VERSION 5.8 ;
BUSBITCHARS "[]" ;
DIVIDERCHAR "/" ;
UNITS
    DATABASE MICRONS 1000 ;
END UNITS

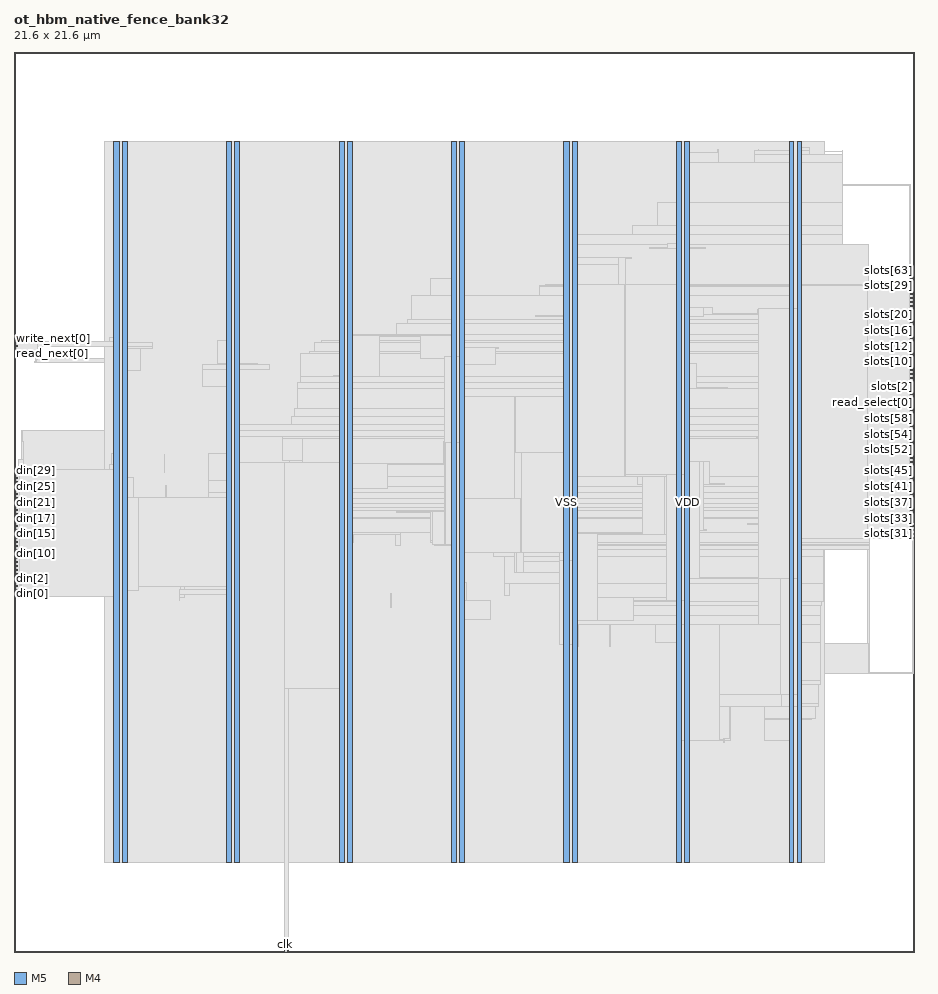
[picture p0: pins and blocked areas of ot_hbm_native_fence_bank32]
MACRO ot_hbm_native_fence_bank32
  FOREIGN ot_hbm_native_fence_bank32 0 0 ;
  CLASS BLOCK ;
  SIZE 21.6 BY 21.6 ;
  PIN clk
    DIRECTION INPUT ;
    USE SIGNAL ;
    PORT
      LAYER M5 ;
        RECT  6.48 0 6.504 0.084 ;
    END
  END clk
  PIN din[0]
    DIRECTION INPUT ;
    USE SIGNAL ;
    PORT
      LAYER M4 ;
        RECT  0 8.592 0.084 8.616 ;
    END
  END din[0]
  PIN din[10]
    DIRECTION INPUT ;
    USE SIGNAL ;
    PORT
      LAYER M4 ;
        RECT  0 9.552 0.084 9.576 ;
    END
  END din[10]
  PIN din[11]
    DIRECTION INPUT ;
    USE SIGNAL ;
    PORT
      LAYER M4 ;
        RECT  0 9.648 0.084 9.672 ;
    END
  END din[11]
  PIN din[12]
    DIRECTION INPUT ;
    USE SIGNAL ;
    PORT
      LAYER M4 ;
        RECT  0 9.744 0.084 9.768 ;
    END
  END din[12]
  PIN din[13]
    DIRECTION INPUT ;
    USE SIGNAL ;
    PORT
      LAYER M4 ;
        RECT  0 9.84 0.084 9.864 ;
    END
  END din[13]
  PIN din[14]
    DIRECTION INPUT ;
    USE SIGNAL ;
    PORT
      LAYER M4 ;
        RECT  0 9.936 0.084 9.96 ;
    END
  END din[14]
  PIN din[15]
    DIRECTION INPUT ;
    USE SIGNAL ;
    PORT
      LAYER M4 ;
        RECT  0 10.032 0.084 10.056 ;
    END
  END din[15]
  PIN din[16]
    DIRECTION INPUT ;
    USE SIGNAL ;
    PORT
      LAYER M4 ;
        RECT  0 10.128 0.084 10.152 ;
    END
  END din[16]
  PIN din[17]
    DIRECTION INPUT ;
    USE SIGNAL ;
    PORT
      LAYER M4 ;
        RECT  0 10.224 0.084 10.248 ;
    END
  END din[17]
  PIN din[18]
    DIRECTION INPUT ;
    USE SIGNAL ;
    PORT
      LAYER M4 ;
        RECT  0 10.32 0.084 10.344 ;
    END
  END din[18]
  PIN din[19]
    DIRECTION INPUT ;
    USE SIGNAL ;
    PORT
      LAYER M4 ;
        RECT  0 10.416 0.084 10.44 ;
    END
  END din[19]
  PIN din[1]
    DIRECTION INPUT ;
    USE SIGNAL ;
    PORT
      LAYER M4 ;
        RECT  0 8.688 0.084 8.712 ;
    END
  END din[1]
  PIN din[20]
    DIRECTION INPUT ;
    USE SIGNAL ;
    PORT
      LAYER M4 ;
        RECT  0 10.512 0.084 10.536 ;
    END
  END din[20]
  PIN din[21]
    DIRECTION INPUT ;
    USE SIGNAL ;
    PORT
      LAYER M4 ;
        RECT  0 10.608 0.084 10.632 ;
    END
  END din[21]
  PIN din[22]
    DIRECTION INPUT ;
    USE SIGNAL ;
    PORT
      LAYER M4 ;
        RECT  0 10.704 0.084 10.728 ;
    END
  END din[22]
  PIN din[23]
    DIRECTION INPUT ;
    USE SIGNAL ;
    PORT
      LAYER M4 ;
        RECT  0 10.8 0.084 10.824 ;
    END
  END din[23]
  PIN din[24]
    DIRECTION INPUT ;
    USE SIGNAL ;
    PORT
      LAYER M4 ;
        RECT  0 10.896 0.084 10.92 ;
    END
  END din[24]
  PIN din[25]
    DIRECTION INPUT ;
    USE SIGNAL ;
    PORT
      LAYER M4 ;
        RECT  0 10.992 0.084 11.016 ;
    END
  END din[25]
  PIN din[26]
    DIRECTION INPUT ;
    USE SIGNAL ;
    PORT
      LAYER M4 ;
        RECT  0 11.088 0.084 11.112 ;
    END
  END din[26]
  PIN din[27]
    DIRECTION INPUT ;
    USE SIGNAL ;
    PORT
      LAYER M4 ;
        RECT  0 11.184 0.084 11.208 ;
    END
  END din[27]
  PIN din[28]
    DIRECTION INPUT ;
    USE SIGNAL ;
    PORT
      LAYER M4 ;
        RECT  0 11.28 0.084 11.304 ;
    END
  END din[28]
  PIN din[29]
    DIRECTION INPUT ;
    USE SIGNAL ;
    PORT
      LAYER M4 ;
        RECT  0 11.376 0.084 11.4 ;
    END
  END din[29]
  PIN din[2]
    DIRECTION INPUT ;
    USE SIGNAL ;
    PORT
      LAYER M4 ;
        RECT  0 8.784 0.084 8.808 ;
    END
  END din[2]
  PIN din[30]
    DIRECTION INPUT ;
    USE SIGNAL ;
    PORT
      LAYER M4 ;
        RECT  0 11.472 0.084 11.496 ;
    END
  END din[30]
  PIN din[31]
    DIRECTION INPUT ;
    USE SIGNAL ;
    PORT
      LAYER M4 ;
        RECT  0 11.568 0.084 11.592 ;
    END
  END din[31]
  PIN din[3]
    DIRECTION INPUT ;
    USE SIGNAL ;
    PORT
      LAYER M4 ;
        RECT  0 8.88 0.084 8.904 ;
    END
  END din[3]
  PIN din[4]
    DIRECTION INPUT ;
    USE SIGNAL ;
    PORT
      LAYER M4 ;
        RECT  0 8.976 0.084 9 ;
    END
  END din[4]
  PIN din[5]
    DIRECTION INPUT ;
    USE SIGNAL ;
    PORT
      LAYER M4 ;
        RECT  0 9.072 0.084 9.096 ;
    END
  END din[5]
  PIN din[6]
    DIRECTION INPUT ;
    USE SIGNAL ;
    PORT
      LAYER M4 ;
        RECT  0 9.168 0.084 9.192 ;
    END
  END din[6]
  PIN din[7]
    DIRECTION INPUT ;
    USE SIGNAL ;
    PORT
      LAYER M4 ;
        RECT  0 9.264 0.084 9.288 ;
    END
  END din[7]
  PIN din[8]
    DIRECTION INPUT ;
    USE SIGNAL ;
    PORT
      LAYER M4 ;
        RECT  0 9.36 0.084 9.384 ;
    END
  END din[8]
  PIN din[9]
    DIRECTION INPUT ;
    USE SIGNAL ;
    PORT
      LAYER M4 ;
        RECT  0 9.456 0.084 9.48 ;
    END
  END din[9]
  PIN read_next[0]
    DIRECTION INPUT ;
    USE SIGNAL ;
    PORT
      LAYER M4 ;
        RECT  0 14.352 0.084 14.376 ;
    END
  END read_next[0]
  PIN read_next[1]
    DIRECTION INPUT ;
    USE SIGNAL ;
    PORT
      LAYER M4 ;
        RECT  0 14.448 0.084 14.472 ;
    END
  END read_next[1]
  PIN read_select[0]
    DIRECTION OUTPUT ;
    USE SIGNAL ;
    PORT
      LAYER M4 ;
        RECT  21.516 13.008 21.6 13.032 ;
    END
  END read_select[0]
  PIN read_select[1]
    DIRECTION OUTPUT ;
    USE SIGNAL ;
    PORT
      LAYER M4 ;
        RECT  21.516 13.104 21.6 13.128 ;
    END
  END read_select[1]
  PIN rst_n
    DIRECTION INPUT ;
    USE SIGNAL ;
    PORT
      LAYER M5 ;
        RECT  6.576 0 6.6 0.084 ;
    END
  END rst_n
  PIN slots[0]
    DIRECTION OUTPUT ;
    USE SIGNAL ;
    PORT
      LAYER M4 ;
        RECT  21.516 13.2 21.6 13.224 ;
    END
  END slots[0]
  PIN slots[10]
    DIRECTION OUTPUT ;
    USE SIGNAL ;
    PORT
      LAYER M4 ;
        RECT  21.516 14.16 21.6 14.184 ;
    END
  END slots[10]
  PIN slots[11]
    DIRECTION OUTPUT ;
    USE SIGNAL ;
    PORT
      LAYER M4 ;
        RECT  21.516 14.256 21.6 14.28 ;
    END
  END slots[11]
  PIN slots[12]
    DIRECTION OUTPUT ;
    USE SIGNAL ;
    PORT
      LAYER M4 ;
        RECT  21.516 14.352 21.6 14.376 ;
    END
  END slots[12]
  PIN slots[13]
    DIRECTION OUTPUT ;
    USE SIGNAL ;
    PORT
      LAYER M4 ;
        RECT  21.516 14.448 21.6 14.472 ;
    END
  END slots[13]
  PIN slots[14]
    DIRECTION OUTPUT ;
    USE SIGNAL ;
    PORT
      LAYER M4 ;
        RECT  21.516 14.544 21.6 14.568 ;
    END
  END slots[14]
  PIN slots[15]
    DIRECTION OUTPUT ;
    USE SIGNAL ;
    PORT
      LAYER M4 ;
        RECT  21.516 14.64 21.6 14.664 ;
    END
  END slots[15]
  PIN slots[16]
    DIRECTION OUTPUT ;
    USE SIGNAL ;
    PORT
      LAYER M4 ;
        RECT  21.516 14.736 21.6 14.76 ;
    END
  END slots[16]
  PIN slots[17]
    DIRECTION OUTPUT ;
    USE SIGNAL ;
    PORT
      LAYER M4 ;
        RECT  21.516 14.832 21.6 14.856 ;
    END
  END slots[17]
  PIN slots[18]
    DIRECTION OUTPUT ;
    USE SIGNAL ;
    PORT
      LAYER M4 ;
        RECT  21.516 14.928 21.6 14.952 ;
    END
  END slots[18]
  PIN slots[19]
    DIRECTION OUTPUT ;
    USE SIGNAL ;
    PORT
      LAYER M4 ;
        RECT  21.516 15.024 21.6 15.048 ;
    END
  END slots[19]
  PIN slots[1]
    DIRECTION OUTPUT ;
    USE SIGNAL ;
    PORT
      LAYER M4 ;
        RECT  21.516 13.296 21.6 13.32 ;
    END
  END slots[1]
  PIN slots[20]
    DIRECTION OUTPUT ;
    USE SIGNAL ;
    PORT
      LAYER M4 ;
        RECT  21.516 15.12 21.6 15.144 ;
    END
  END slots[20]
  PIN slots[21]
    DIRECTION OUTPUT ;
    USE SIGNAL ;
    PORT
      LAYER M4 ;
        RECT  21.516 15.216 21.6 15.24 ;
    END
  END slots[21]
  PIN slots[22]
    DIRECTION OUTPUT ;
    USE SIGNAL ;
    PORT
      LAYER M4 ;
        RECT  21.516 15.312 21.6 15.336 ;
    END
  END slots[22]
  PIN slots[23]
    DIRECTION OUTPUT ;
    USE SIGNAL ;
    PORT
      LAYER M4 ;
        RECT  21.516 15.408 21.6 15.432 ;
    END
  END slots[23]
  PIN slots[24]
    DIRECTION OUTPUT ;
    USE SIGNAL ;
    PORT
      LAYER M4 ;
        RECT  21.516 15.504 21.6 15.528 ;
    END
  END slots[24]
  PIN slots[25]
    DIRECTION OUTPUT ;
    USE SIGNAL ;
    PORT
      LAYER M4 ;
        RECT  21.516 15.6 21.6 15.624 ;
    END
  END slots[25]
  PIN slots[26]
    DIRECTION OUTPUT ;
    USE SIGNAL ;
    PORT
      LAYER M4 ;
        RECT  21.516 15.696 21.6 15.72 ;
    END
  END slots[26]
  PIN slots[27]
    DIRECTION OUTPUT ;
    USE SIGNAL ;
    PORT
      LAYER M4 ;
        RECT  21.516 15.792 21.6 15.816 ;
    END
  END slots[27]
  PIN slots[28]
    DIRECTION OUTPUT ;
    USE SIGNAL ;
    PORT
      LAYER M4 ;
        RECT  21.516 15.888 21.6 15.912 ;
    END
  END slots[28]
  PIN slots[29]
    DIRECTION OUTPUT ;
    USE SIGNAL ;
    PORT
      LAYER M4 ;
        RECT  21.516 15.984 21.6 16.008 ;
    END
  END slots[29]
  PIN slots[2]
    DIRECTION OUTPUT ;
    USE SIGNAL ;
    PORT
      LAYER M4 ;
        RECT  21.516 13.392 21.6 13.416 ;
    END
  END slots[2]
  PIN slots[30]
    DIRECTION OUTPUT ;
    USE SIGNAL ;
    PORT
      LAYER M4 ;
        RECT  21.516 9.936 21.6 9.96 ;
    END
  END slots[30]
  PIN slots[31]
    DIRECTION OUTPUT ;
    USE SIGNAL ;
    PORT
      LAYER M4 ;
        RECT  21.516 10.032 21.6 10.056 ;
    END
  END slots[31]
  PIN slots[32]
    DIRECTION OUTPUT ;
    USE SIGNAL ;
    PORT
      LAYER M4 ;
        RECT  21.516 10.128 21.6 10.152 ;
    END
  END slots[32]
  PIN slots[33]
    DIRECTION OUTPUT ;
    USE SIGNAL ;
    PORT
      LAYER M4 ;
        RECT  21.516 10.224 21.6 10.248 ;
    END
  END slots[33]
  PIN slots[34]
    DIRECTION OUTPUT ;
    USE SIGNAL ;
    PORT
      LAYER M4 ;
        RECT  21.516 10.32 21.6 10.344 ;
    END
  END slots[34]
  PIN slots[35]
    DIRECTION OUTPUT ;
    USE SIGNAL ;
    PORT
      LAYER M4 ;
        RECT  21.516 10.416 21.6 10.44 ;
    END
  END slots[35]
  PIN slots[36]
    DIRECTION OUTPUT ;
    USE SIGNAL ;
    PORT
      LAYER M4 ;
        RECT  21.516 10.512 21.6 10.536 ;
    END
  END slots[36]
  PIN slots[37]
    DIRECTION OUTPUT ;
    USE SIGNAL ;
    PORT
      LAYER M4 ;
        RECT  21.516 10.608 21.6 10.632 ;
    END
  END slots[37]
  PIN slots[38]
    DIRECTION OUTPUT ;
    USE SIGNAL ;
    PORT
      LAYER M4 ;
        RECT  21.516 10.704 21.6 10.728 ;
    END
  END slots[38]
  PIN slots[39]
    DIRECTION OUTPUT ;
    USE SIGNAL ;
    PORT
      LAYER M4 ;
        RECT  21.516 10.8 21.6 10.824 ;
    END
  END slots[39]
  PIN slots[3]
    DIRECTION OUTPUT ;
    USE SIGNAL ;
    PORT
      LAYER M4 ;
        RECT  21.516 13.488 21.6 13.512 ;
    END
  END slots[3]
  PIN slots[40]
    DIRECTION OUTPUT ;
    USE SIGNAL ;
    PORT
      LAYER M4 ;
        RECT  21.516 10.896 21.6 10.92 ;
    END
  END slots[40]
  PIN slots[41]
    DIRECTION OUTPUT ;
    USE SIGNAL ;
    PORT
      LAYER M4 ;
        RECT  21.516 10.992 21.6 11.016 ;
    END
  END slots[41]
  PIN slots[42]
    DIRECTION OUTPUT ;
    USE SIGNAL ;
    PORT
      LAYER M4 ;
        RECT  21.516 11.088 21.6 11.112 ;
    END
  END slots[42]
  PIN slots[43]
    DIRECTION OUTPUT ;
    USE SIGNAL ;
    PORT
      LAYER M4 ;
        RECT  21.516 11.184 21.6 11.208 ;
    END
  END slots[43]
  PIN slots[44]
    DIRECTION OUTPUT ;
    USE SIGNAL ;
    PORT
      LAYER M4 ;
        RECT  21.516 11.28 21.6 11.304 ;
    END
  END slots[44]
  PIN slots[45]
    DIRECTION OUTPUT ;
    USE SIGNAL ;
    PORT
      LAYER M4 ;
        RECT  21.516 11.376 21.6 11.4 ;
    END
  END slots[45]
  PIN slots[46]
    DIRECTION OUTPUT ;
    USE SIGNAL ;
    PORT
      LAYER M4 ;
        RECT  21.516 11.472 21.6 11.496 ;
    END
  END slots[46]
  PIN slots[47]
    DIRECTION OUTPUT ;
    USE SIGNAL ;
    PORT
      LAYER M4 ;
        RECT  21.516 11.568 21.6 11.592 ;
    END
  END slots[47]
  PIN slots[48]
    DIRECTION OUTPUT ;
    USE SIGNAL ;
    PORT
      LAYER M4 ;
        RECT  21.516 11.664 21.6 11.688 ;
    END
  END slots[48]
  PIN slots[49]
    DIRECTION OUTPUT ;
    USE SIGNAL ;
    PORT
      LAYER M4 ;
        RECT  21.516 11.76 21.6 11.784 ;
    END
  END slots[49]
  PIN slots[4]
    DIRECTION OUTPUT ;
    USE SIGNAL ;
    PORT
      LAYER M4 ;
        RECT  21.516 13.584 21.6 13.608 ;
    END
  END slots[4]
  PIN slots[50]
    DIRECTION OUTPUT ;
    USE SIGNAL ;
    PORT
      LAYER M4 ;
        RECT  21.516 11.856 21.6 11.88 ;
    END
  END slots[50]
  PIN slots[51]
    DIRECTION OUTPUT ;
    USE SIGNAL ;
    PORT
      LAYER M4 ;
        RECT  21.516 11.952 21.6 11.976 ;
    END
  END slots[51]
  PIN slots[52]
    DIRECTION OUTPUT ;
    USE SIGNAL ;
    PORT
      LAYER M4 ;
        RECT  21.516 12.048 21.6 12.072 ;
    END
  END slots[52]
  PIN slots[53]
    DIRECTION OUTPUT ;
    USE SIGNAL ;
    PORT
      LAYER M4 ;
        RECT  21.516 12.144 21.6 12.168 ;
    END
  END slots[53]
  PIN slots[54]
    DIRECTION OUTPUT ;
    USE SIGNAL ;
    PORT
      LAYER M4 ;
        RECT  21.516 12.24 21.6 12.264 ;
    END
  END slots[54]
  PIN slots[55]
    DIRECTION OUTPUT ;
    USE SIGNAL ;
    PORT
      LAYER M4 ;
        RECT  21.516 12.336 21.6 12.36 ;
    END
  END slots[55]
  PIN slots[56]
    DIRECTION OUTPUT ;
    USE SIGNAL ;
    PORT
      LAYER M4 ;
        RECT  21.516 12.432 21.6 12.456 ;
    END
  END slots[56]
  PIN slots[57]
    DIRECTION OUTPUT ;
    USE SIGNAL ;
    PORT
      LAYER M4 ;
        RECT  21.516 12.528 21.6 12.552 ;
    END
  END slots[57]
  PIN slots[58]
    DIRECTION OUTPUT ;
    USE SIGNAL ;
    PORT
      LAYER M4 ;
        RECT  21.516 12.624 21.6 12.648 ;
    END
  END slots[58]
  PIN slots[59]
    DIRECTION OUTPUT ;
    USE SIGNAL ;
    PORT
      LAYER M4 ;
        RECT  21.516 12.72 21.6 12.744 ;
    END
  END slots[59]
  PIN slots[5]
    DIRECTION OUTPUT ;
    USE SIGNAL ;
    PORT
      LAYER M4 ;
        RECT  21.516 13.68 21.6 13.704 ;
    END
  END slots[5]
  PIN slots[60]
    DIRECTION OUTPUT ;
    USE SIGNAL ;
    PORT
      LAYER M4 ;
        RECT  21.516 12.816 21.6 12.84 ;
    END
  END slots[60]
  PIN slots[61]
    DIRECTION OUTPUT ;
    USE SIGNAL ;
    PORT
      LAYER M4 ;
        RECT  21.516 12.912 21.6 12.936 ;
    END
  END slots[61]
  PIN slots[62]
    DIRECTION OUTPUT ;
    USE SIGNAL ;
    PORT
      LAYER M4 ;
        RECT  21.516 16.08 21.6 16.104 ;
    END
  END slots[62]
  PIN slots[63]
    DIRECTION OUTPUT ;
    USE SIGNAL ;
    PORT
      LAYER M4 ;
        RECT  21.516 16.176 21.6 16.2 ;
    END
  END slots[63]
  PIN slots[6]
    DIRECTION OUTPUT ;
    USE SIGNAL ;
    PORT
      LAYER M4 ;
        RECT  21.516 13.776 21.6 13.8 ;
    END
  END slots[6]
  PIN slots[7]
    DIRECTION OUTPUT ;
    USE SIGNAL ;
    PORT
      LAYER M4 ;
        RECT  21.516 13.872 21.6 13.896 ;
    END
  END slots[7]
  PIN slots[8]
    DIRECTION OUTPUT ;
    USE SIGNAL ;
    PORT
      LAYER M4 ;
        RECT  21.516 13.968 21.6 13.992 ;
    END
  END slots[8]
  PIN slots[9]
    DIRECTION OUTPUT ;
    USE SIGNAL ;
    PORT
      LAYER M4 ;
        RECT  21.516 14.064 21.6 14.088 ;
    END
  END slots[9]
  PIN write_next[0]
    DIRECTION INPUT ;
    USE SIGNAL ;
    PORT
      LAYER M4 ;
        RECT  0 14.544 0.084 14.568 ;
    END
  END write_next[0]
  PIN write_next[1]
    DIRECTION INPUT ;
    USE SIGNAL ;
    PORT
      LAYER M4 ;
        RECT  0 14.64 0.084 14.664 ;
    END
  END write_next[1]
  PIN VDD
    DIRECTION INOUT ;
    USE POWER ;
    PORT
      LAYER M5 ;
        RECT  18.792 2.151 18.912 19.449 ;
        RECT  16.092 2.151 16.212 19.449 ;
        RECT  13.392 2.151 13.512 19.449 ;
        RECT  10.692 2.151 10.812 19.449 ;
        RECT  7.992 2.151 8.112 19.449 ;
        RECT  5.292 2.151 5.412 19.449 ;
        RECT  2.592 2.151 2.712 19.449 ;
    END
  END VDD
  PIN VSS
    DIRECTION INOUT ;
    USE GROUND ;
    PORT
      LAYER M5 ;
        RECT  18.6 2.137 18.72 19.463 ;
        RECT  15.9 2.137 16.02 19.463 ;
        RECT  13.2 2.137 13.32 19.463 ;
        RECT  10.5 2.137 10.62 19.463 ;
        RECT  7.8 2.137 7.92 19.463 ;
        RECT  5.1 2.137 5.22 19.463 ;
        RECT  2.4 2.137 2.52 19.463 ;
    END
  END VSS
  # OT_OBS_CLOSED layer=M5 d_um=1.536 added=15
  OBS
    LAYER RVTN ;
     RECT  2.16 2.16 19.44 2.295 ;
     RECT  2.16 2.565 19.44 2.835 ;
     RECT  2.16 3.105 19.44 3.375 ;
     RECT  2.16 3.645 19.44 3.915 ;
     RECT  2.16 4.185 19.44 4.455 ;
     RECT  2.16 4.725 19.44 4.995 ;
     RECT  2.16 5.265 19.44 5.535 ;
     RECT  2.16 5.805 19.44 6.075 ;
     RECT  2.16 6.345 19.44 6.615 ;
     RECT  2.16 6.885 19.44 7.155 ;
     RECT  2.16 7.425 19.44 7.695 ;
     RECT  2.16 7.965 19.44 8.235 ;
     RECT  2.16 8.505 19.44 8.775 ;
     RECT  2.16 9.045 19.44 9.315 ;
     RECT  2.16 9.585 19.44 9.855 ;
     RECT  2.16 10.125 19.44 10.395 ;
     RECT  2.16 10.665 19.44 10.935 ;
     RECT  2.16 11.205 19.44 11.475 ;
     RECT  2.16 11.745 19.44 12.015 ;
     RECT  2.16 12.285 19.44 12.555 ;
     RECT  2.16 12.825 19.44 13.095 ;
     RECT  2.16 13.365 19.44 13.635 ;
     RECT  2.16 13.905 19.44 14.175 ;
     RECT  2.16 14.445 19.44 14.715 ;
     RECT  2.16 14.985 19.44 15.255 ;
     RECT  2.16 15.525 19.44 15.795 ;
     RECT  2.16 16.065 19.44 16.335 ;
     RECT  2.16 16.605 19.44 16.875 ;
     RECT  2.16 17.145 19.44 17.415 ;
     RECT  2.16 17.685 19.44 17.955 ;
     RECT  2.16 18.225 19.44 18.495 ;
     RECT  2.16 18.765 19.44 19.035 ;
     RECT  2.16 19.305 19.44 19.44 ;
    LAYER RVTP ;
     RECT  2.16 2.295 19.44 2.565 ;
     RECT  2.16 2.835 19.44 3.105 ;
     RECT  2.16 3.375 19.44 3.645 ;
     RECT  2.16 3.915 19.44 4.185 ;
     RECT  2.16 4.455 19.44 4.725 ;
     RECT  2.16 4.995 19.44 5.265 ;
     RECT  2.16 5.535 19.44 5.805 ;
     RECT  2.16 6.075 19.44 6.345 ;
     RECT  2.16 6.615 19.44 6.885 ;
     RECT  2.16 7.155 19.44 7.425 ;
     RECT  2.16 7.695 19.44 7.965 ;
     RECT  2.16 8.235 19.44 8.505 ;
     RECT  2.16 8.775 19.44 9.045 ;
     RECT  2.16 9.315 19.44 9.585 ;
     RECT  2.16 9.855 19.44 10.125 ;
     RECT  2.16 10.395 19.44 10.665 ;
     RECT  2.16 10.935 19.44 11.205 ;
     RECT  2.16 11.475 19.44 11.745 ;
     RECT  2.16 12.015 19.44 12.285 ;
     RECT  2.16 12.555 19.44 12.825 ;
     RECT  2.16 13.095 19.44 13.365 ;
     RECT  2.16 13.635 19.44 13.905 ;
     RECT  2.16 14.175 19.44 14.445 ;
     RECT  2.16 14.715 19.44 14.985 ;
     RECT  2.16 15.255 19.44 15.525 ;
     RECT  2.16 15.795 19.44 16.065 ;
     RECT  2.16 16.335 19.44 16.605 ;
     RECT  2.16 16.875 19.44 17.145 ;
     RECT  2.16 17.415 19.44 17.685 ;
     RECT  2.16 17.955 19.44 18.225 ;
     RECT  2.16 18.495 19.44 18.765 ;
     RECT  2.16 19.035 19.44 19.305 ;
    LAYER M1 ;
     RECT  2.16 2.151 19.44 19.449 ;
    LAYER M2 ;
     RECT  0.103 9.486 0.139 9.504 ;
     RECT  0.103 11.79 0.139 11.808 ;
     RECT  0.139 11.484 0.175 11.808 ;
     RECT  0.139 8.856 0.239 9.504 ;
     RECT  0.499 14.148 0.535 14.166 ;
     RECT  0.239 9.486 2.16 9.504 ;
     RECT  0.175 11.484 2.16 12.51 ;
     RECT  0.535 14.148 2.16 14.238 ;
     RECT  2.16 2.151 19.44 19.449 ;
     RECT  19.44 19.206 19.895 19.224 ;
     RECT  19.44 9.666 19.967 16.974 ;
     RECT  19.967 10.206 20.219 16.974 ;
     RECT  20.219 14.346 20.471 16.974 ;
     RECT  19.44 6.696 20.507 7.416 ;
     RECT  20.219 10.206 20.507 13.554 ;
     RECT  20.471 14.346 20.507 15.984 ;
     RECT  20.471 16.956 20.507 16.974 ;
     RECT  20.507 6.696 20.543 7.344 ;
     RECT  20.507 12.366 20.579 13.554 ;
     RECT  20.507 10.206 21.479 10.728 ;
     RECT  20.579 12.366 21.479 12.888 ;
     RECT  21.479 10.296 21.515 10.728 ;
     RECT  21.479 12.87 21.515 12.888 ;
     RECT  20.507 15.498 21.515 15.516 ;
     RECT  19.44 18.396 21.515 18.414 ;
     RECT  20.543 6.696 21.587 6.714 ;
     RECT  21.515 10.296 21.587 10.314 ;
    LAYER M3 ;
     RECT  2.415 2.143 2.505 2.413 ;
     RECT  5.115 2.143 5.205 2.413 ;
     RECT  7.815 2.143 7.905 2.413 ;
     RECT  10.515 2.143 10.605 2.413 ;
     RECT  13.215 2.143 13.305 2.413 ;
     RECT  15.915 2.143 16.005 2.413 ;
     RECT  18.615 2.143 18.705 2.413 ;
     RECT  17.028 5.035 17.046 5.071 ;
     RECT  18.615 2.413 18.897 5.071 ;
     RECT  17.028 5.071 17.19 5.117 ;
     RECT  18 5.071 18.897 5.575 ;
     RECT  18 5.575 19.134 5.611 ;
     RECT  18 5.611 19.242 5.881 ;
     RECT  17.172 5.117 17.19 5.971 ;
     RECT  18 5.881 19.314 5.971 ;
     RECT  17.172 5.971 19.314 6.421 ;
     RECT  15.915 2.413 16.197 6.523 ;
     RECT  16.92 6.421 19.35 6.523 ;
     RECT  6.624 6.283 6.642 6.575 ;
     RECT  13.215 2.413 13.497 7.321 ;
     RECT  20.52 7.321 20.538 7.393 ;
     RECT  15.915 6.523 19.35 7.429 ;
     RECT  13.215 7.321 13.554 7.501 ;
     RECT  13.104 7.501 13.554 7.861 ;
     RECT  14.292 7.321 14.31 7.861 ;
     RECT  15.408 7.429 19.35 7.861 ;
     RECT  10.515 2.413 10.797 7.969 ;
     RECT  13.104 7.861 19.35 8.069 ;
     RECT  13.176 8.069 19.35 8.311 ;
     RECT  13.176 8.311 19.386 8.401 ;
     RECT  10.515 7.969 11.43 8.429 ;
     RECT  6.732 6.691 6.75 8.473 ;
     RECT  3.96 8.437 3.978 8.509 ;
     RECT  2.415 2.413 2.697 8.539 ;
     RECT  3.96 8.509 4.086 8.581 ;
     RECT  5.115 2.413 5.397 8.581 ;
     RECT  2.415 8.539 2.718 8.587 ;
     RECT  9.036 8.275 9.054 8.609 ;
     RECT  2.304 8.587 2.718 8.683 ;
     RECT  3.96 8.581 5.397 8.699 ;
     RECT  6.696 8.473 6.75 8.779 ;
     RECT  0.324 8.683 0.342 8.813 ;
     RECT  6.516 8.779 6.75 8.827 ;
     RECT  0.216 8.827 0.234 8.851 ;
     RECT  6.516 8.827 6.786 8.851 ;
     RECT  11.772 8.545 11.898 8.851 ;
     RECT  13.176 8.401 19.422 8.851 ;
     RECT  0.144 8.851 0.234 8.879 ;
     RECT  10.515 8.429 10.854 8.879 ;
     RECT  0.144 8.879 0.162 8.909 ;
     RECT  3.996 8.699 4.086 8.909 ;
     RECT  4.068 8.909 4.086 8.969 ;
     RECT  5.115 8.699 5.397 9.085 ;
     RECT  6.516 8.851 7.002 9.085 ;
     RECT  2.304 8.683 2.97 9.121 ;
     RECT  2.268 9.121 2.97 9.197 ;
     RECT  5.115 9.085 7.002 9.239 ;
     RECT  2.304 9.197 2.97 9.283 ;
     RECT  2.304 9.283 3.006 9.389 ;
     RECT  5.115 9.239 6.93 9.481 ;
     RECT  11.772 8.851 19.422 9.481 ;
     RECT  0.108 9.451 0.126 9.509 ;
     RECT  2.304 9.389 2.862 9.629 ;
     RECT  11.52 9.481 19.422 9.661 ;
     RECT  20.484 7.393 20.538 9.661 ;
     RECT  4.464 9.481 6.93 9.689 ;
     RECT  10.515 8.879 10.797 9.751 ;
     RECT  11.52 9.661 20.538 9.751 ;
     RECT  10.08 9.751 20.538 9.787 ;
     RECT  7.815 2.413 8.097 9.823 ;
     RECT  10.044 9.787 20.538 9.823 ;
     RECT  7.815 9.823 8.154 10.021 ;
     RECT  9.144 9.751 9.27 10.021 ;
     RECT  4.464 9.689 5.922 10.027 ;
     RECT  7.815 10.021 9.27 10.057 ;
     RECT  10.008 9.823 20.538 10.057 ;
     RECT  4.356 10.027 5.922 10.123 ;
     RECT  21.564 6.691 21.582 10.201 ;
     RECT  21.456 10.201 21.582 10.319 ;
     RECT  7.815 10.057 20.538 10.399 ;
     RECT  4.032 10.123 5.922 10.411 ;
     RECT  6.732 9.689 6.93 10.411 ;
     RECT  4.032 10.411 6.93 10.435 ;
     RECT  7.815 10.399 20.646 10.435 ;
     RECT  21.456 10.319 21.51 10.445 ;
     RECT  4.032 10.435 20.646 10.603 ;
     RECT  2.304 9.629 2.697 10.669 ;
     RECT  3.996 10.603 20.646 10.669 ;
     RECT  21.492 10.445 21.51 10.733 ;
     RECT  2.304 10.669 20.646 10.769 ;
     RECT  3.636 10.769 20.646 10.895 ;
     RECT  4.68 10.895 20.646 11.039 ;
     RECT  0.144 10.651 0.162 11.083 ;
     RECT  6.624 11.039 20.646 11.165 ;
     RECT  3.636 10.895 3.654 11.201 ;
     RECT  0.108 11.083 0.162 11.275 ;
     RECT  4.68 11.039 5.778 11.309 ;
     RECT  0.108 11.275 0.198 11.371 ;
     RECT  2.304 10.769 2.862 11.399 ;
     RECT  6.624 11.165 7.038 11.399 ;
     RECT  7.815 11.165 20.646 11.405 ;
     RECT  2.304 11.399 2.697 11.705 ;
     RECT  6.624 11.399 6.93 11.785 ;
     RECT  0.108 11.371 0.234 11.813 ;
     RECT  3.6 11.515 3.618 11.939 ;
     RECT  2.34 11.705 2.697 11.975 ;
     RECT  4.68 11.309 5.397 11.975 ;
     RECT  0.18 11.813 0.234 12.245 ;
     RECT  6.444 11.785 6.93 12.325 ;
     RECT  7.815 11.405 20.502 12.325 ;
     RECT  5.115 11.975 5.397 12.361 ;
     RECT  6.444 12.325 20.502 12.361 ;
     RECT  21.456 12.361 21.474 12.427 ;
     RECT  0.18 12.245 0.198 12.515 ;
     RECT  5.115 12.361 20.502 12.523 ;
     RECT  21.456 12.427 21.51 12.557 ;
     RECT  5.115 12.523 20.538 12.659 ;
     RECT  6.66 12.659 20.538 12.857 ;
     RECT  21.492 12.557 21.51 12.893 ;
     RECT  6.732 12.857 20.538 13.055 ;
     RECT  6.804 13.055 20.538 13.531 ;
     RECT  5.115 12.659 5.397 13.567 ;
     RECT  6.804 13.531 20.574 13.667 ;
     RECT  6.876 13.667 20.574 13.805 ;
     RECT  2.415 11.975 2.697 13.945 ;
     RECT  4.536 13.567 5.397 13.981 ;
     RECT  4.536 13.981 6.138 14.099 ;
     RECT  4.896 14.099 5.85 14.135 ;
     RECT  0.504 14.143 0.522 14.215 ;
     RECT  6.876 13.805 20.502 14.369 ;
     RECT  0.504 14.215 0.558 14.381 ;
     RECT  7.092 14.369 20.502 14.405 ;
     RECT  0.504 14.381 0.522 14.477 ;
     RECT  2.415 13.945 3.042 14.485 ;
     RECT  2.415 14.485 3.33 14.539 ;
     RECT  2.304 14.539 3.33 14.639 ;
     RECT  7.2 14.405 20.502 14.639 ;
     RECT  4.896 14.135 5.397 14.675 ;
     RECT  7.38 14.639 20.502 14.675 ;
     RECT  2.304 14.639 2.697 14.747 ;
     RECT  7.815 14.675 20.502 14.819 ;
     RECT  9.18 14.819 20.502 15.089 ;
     RECT  9.432 15.089 19.494 15.179 ;
     RECT  9.54 15.179 19.494 15.755 ;
     RECT  12.6 15.755 19.494 15.979 ;
     RECT  20.232 15.089 20.502 15.979 ;
     RECT  12.6 15.979 20.502 15.989 ;
     RECT  12.744 15.989 20.502 16.025 ;
     RECT  10.008 15.755 10.797 16.169 ;
     RECT  13.215 16.025 20.502 16.979 ;
     RECT  13.215 16.979 19.89 17.213 ;
     RECT  14.832 17.213 19.89 17.447 ;
     RECT  15.444 17.447 19.89 17.987 ;
     RECT  21.492 14.155 21.51 18.419 ;
     RECT  15.915 17.987 19.89 18.959 ;
     RECT  17.784 18.959 19.89 19.139 ;
     RECT  2.415 14.747 2.697 19.187 ;
     RECT  5.115 14.675 5.397 19.187 ;
     RECT  7.815 14.819 8.097 19.187 ;
     RECT  10.515 16.169 10.797 19.187 ;
     RECT  13.215 17.213 13.497 19.187 ;
     RECT  15.915 18.959 16.902 19.187 ;
     RECT  17.784 19.139 19.098 19.229 ;
     RECT  19.872 19.139 19.89 19.229 ;
     RECT  16.884 19.187 16.902 19.265 ;
     RECT  17.856 19.229 17.874 19.265 ;
     RECT  18.615 19.229 19.098 19.301 ;
     RECT  2.415 19.187 2.505 19.457 ;
     RECT  5.115 19.187 5.205 19.457 ;
     RECT  7.815 19.187 7.905 19.457 ;
     RECT  10.515 19.187 10.605 19.457 ;
     RECT  13.215 19.187 13.305 19.457 ;
     RECT  15.915 19.187 16.005 19.457 ;
     RECT  18.615 19.301 18.705 19.457 ;
    LAYER M4 ;
     RECT  0.06 8.592 0.133 11.592 ;
     RECT  0.06 14.352 0.569 14.664 ;
     RECT  0.133 8.544 2.408 11.592 ;
     RECT  0.569 14.544 2.408 14.664 ;
     RECT  2.408 2.148 2.512 19.452 ;
     RECT  2.512 2.418 2.704 19.182 ;
     RECT  2.704 8.544 2.729 10.92 ;
     RECT  2.729 8.688 2.981 10.92 ;
     RECT  2.981 8.784 5.108 10.92 ;
     RECT  5.108 2.148 5.212 19.452 ;
     RECT  5.212 2.418 5.404 19.182 ;
     RECT  5.404 8.784 5.681 10.92 ;
     RECT  5.681 8.784 6.257 10.44 ;
     RECT  6.257 8.784 6.329 9.576 ;
     RECT  6.329 8.784 6.545 9.384 ;
     RECT  6.545 8.832 6.581 9.384 ;
     RECT  6.565 6.288 6.653 6.312 ;
     RECT  6.581 8.832 6.797 8.856 ;
     RECT  6.469 11.712 6.865 11.736 ;
     RECT  6.865 11.328 7.808 11.736 ;
     RECT  7.657 13.824 7.808 13.848 ;
     RECT  7.808 2.148 7.912 19.452 ;
     RECT  7.912 2.418 8.104 19.182 ;
     RECT  8.104 13.824 8.777 14.808 ;
     RECT  8.104 11.136 8.957 11.736 ;
     RECT  8.777 14.784 9.745 14.808 ;
     RECT  9.169 10.56 9.997 10.584 ;
     RECT  9.997 9.888 10.033 10.584 ;
     RECT  8.957 11.712 10.309 11.736 ;
     RECT  10.033 9.792 10.321 10.584 ;
     RECT  10.309 11.712 10.321 12.264 ;
     RECT  10.321 9.792 10.357 12.264 ;
     RECT  10.357 9.792 10.508 12.36 ;
     RECT  9.745 14.256 10.508 14.808 ;
     RECT  10.508 2.148 10.612 19.452 ;
     RECT  10.612 2.418 10.804 19.182 ;
     RECT  10.804 14.112 11.549 14.52 ;
     RECT  11.549 14.496 11.621 14.52 ;
     RECT  10.804 10.848 11.837 12.504 ;
     RECT  11.837 10.896 11.989 12.504 ;
     RECT  10.804 9.792 12.013 9.816 ;
     RECT  12.013 9.12 12.053 9.816 ;
     RECT  11.989 10.896 12.061 13.32 ;
     RECT  12.061 10.992 12.161 13.32 ;
     RECT  12.053 9.12 12.22 9.624 ;
     RECT  13.093 7.392 13.208 7.416 ;
     RECT  12.22 9.12 13.208 9.384 ;
     RECT  12.161 11.088 13.208 12.504 ;
     RECT  12.517 15.264 13.208 15.288 ;
     RECT  13.208 2.148 13.312 19.452 ;
     RECT  13.312 2.418 13.504 19.182 ;
     RECT  13.504 11.712 13.781 11.976 ;
     RECT  13.504 7.968 13.997 10.056 ;
     RECT  13.504 13.056 14.285 15.384 ;
     RECT  14.285 14.112 14.497 15.384 ;
     RECT  13.504 16.512 14.497 16.68 ;
     RECT  13.781 11.712 14.629 11.736 ;
     RECT  14.497 14.112 14.675 16.68 ;
     RECT  14.675 16.656 14.825 16.68 ;
     RECT  13.997 7.968 14.861 8.52 ;
     RECT  14.285 13.056 14.861 13.08 ;
     RECT  14.629 11.424 14.965 11.736 ;
     RECT  13.997 10.032 15.073 10.056 ;
     RECT  14.965 11.232 15.073 11.736 ;
     RECT  15.073 10.032 15.613 11.736 ;
     RECT  15.253 16.896 15.685 16.92 ;
     RECT  15.613 10.032 15.757 11.784 ;
     RECT  14.861 8.448 15.908 8.52 ;
     RECT  15.757 9.552 15.908 11.784 ;
     RECT  14.675 14.112 15.908 15.48 ;
     RECT  15.685 16.896 15.908 17.016 ;
     RECT  15.908 2.148 16.012 19.452 ;
     RECT  16.012 2.418 16.204 19.182 ;
     RECT  16.204 13.536 16.373 14.136 ;
     RECT  16.204 8.976 16.445 11.784 ;
     RECT  16.445 10.128 16.553 11.784 ;
     RECT  16.204 15.264 16.553 15.48 ;
     RECT  16.204 16.896 16.589 16.92 ;
     RECT  16.553 10.128 16.625 10.152 ;
     RECT  16.553 11.232 16.697 11.784 ;
     RECT  16.553 15.312 16.769 15.48 ;
     RECT  16.204 6.528 16.931 6.552 ;
     RECT  16.204 7.824 16.931 7.848 ;
     RECT  16.204 5.088 17.057 5.112 ;
     RECT  16.697 11.232 17.057 11.256 ;
     RECT  16.373 13.536 17.129 13.56 ;
     RECT  17.197 7.104 17.597 7.128 ;
     RECT  16.769 15.312 17.845 15.336 ;
     RECT  17.845 15.312 18.241 15.432 ;
     RECT  17.593 10.272 18.373 10.296 ;
     RECT  18.373 6.192 18.421 6.264 ;
     RECT  18.373 10.272 18.421 10.92 ;
     RECT  18.421 10.272 18.565 11.064 ;
     RECT  17.809 12.336 18.565 12.36 ;
     RECT  18.421 5.904 18.608 6.264 ;
     RECT  16.445 8.976 18.608 9 ;
     RECT  18.565 10.272 18.608 12.36 ;
     RECT  18.241 15.024 18.608 15.432 ;
     RECT  18.608 2.148 18.712 19.452 ;
     RECT  18.712 2.418 18.904 19.182 ;
     RECT  18.904 9.936 20.473 16.008 ;
     RECT  20.473 9.936 21.481 16.104 ;
     RECT  21.481 9.936 21.564 16.2 ;
    LAYER M5 ;
     RECT  2.4 2.137 2.52 2.151 ;
     RECT  5.1 2.137 5.22 2.151 ;
     RECT  7.8 2.137 7.92 2.151 ;
     RECT  10.5 2.137 10.62 2.151 ;
     RECT  13.2 2.137 13.32 2.151 ;
     RECT  15.9 2.137 16.02 2.151 ;
     RECT  18.6 2.137 18.72 2.151 ;
     RECT  15.9 2.151 16.212 5.077 ;
     RECT  18.6 2.151 18.912 5.893 ;
     RECT  18.432 5.893 18.912 6.181 ;
     RECT  6.48 0.016 6.6 6.323 ;
     RECT  13.2 2.151 13.512 7.381 ;
     RECT  15.9 5.077 16.92 7.859 ;
     RECT  15.9 7.859 16.212 8.437 ;
     RECT  0.144 8.533 0.168 8.819 ;
     RECT  18.384 6.181 18.912 8.965 ;
     RECT  13.104 7.381 13.512 9.395 ;
     RECT  12.144 9.589 12.168 10.885 ;
     RECT  15.648 8.437 16.212 11.459 ;
     RECT  6.48 6.323 6.504 11.747 ;
     RECT  12 10.885 12.168 11.987 ;
     RECT  10.5 2.151 10.812 12.229 ;
     RECT  12 11.987 12.024 13.331 ;
     RECT  10.32 12.229 10.812 14.291 ;
     RECT  17.856 8.965 18.912 15.443 ;
     RECT  14.64 11.413 14.664 16.019 ;
     RECT  2.4 2.151 2.712 19.449 ;
     RECT  5.1 2.151 5.412 19.449 ;
     RECT  7.8 2.151 8.112 19.449 ;
     RECT  10.5 14.291 10.812 19.449 ;
     RECT  13.2 9.395 13.512 19.449 ;
     RECT  15.9 11.459 16.212 19.449 ;
     RECT  18.6 15.443 18.912 19.449 ;
     RECT  2.4 19.449 2.52 19.463 ;
     RECT  5.1 19.449 5.22 19.463 ;
     RECT  7.8 19.449 7.92 19.463 ;
     RECT  10.5 19.449 10.62 19.463 ;
     RECT  13.2 19.449 13.32 19.463 ;
     RECT  15.9 19.449 16.02 19.463 ;
     RECT  18.6 19.449 18.72 19.463 ;
     RECT  5.22 2.137 6.48 2.151 ;
     RECT  6.6 2.137 7.8 6.323 ;
     RECT  5.412 2.151 6.48 11.747 ;
     RECT  16.92 5.893 18.432 6.181 ;
     RECT  16.92 6.181 18.384 7.859 ;
     RECT  6.504 6.323 7.8 11.747 ;
     RECT  17.856 7.859 18.384 8.965 ;
     RECT  13.104 9.395 13.2 9.589 ;
     RECT  10.812 9.589 12.144 10.885 ;
     RECT  12.168 9.589 13.2 11.987 ;
     RECT  10.812 10.885 12 13.331 ;
     RECT  13.512 11.413 14.64 16.019 ;
     RECT  14.664 11.413 15.648 11.459 ;
     RECT  14.664 11.459 15.9 16.019 ;
     RECT  12.024 11.987 13.2 13.331 ;
  END
END ot_hbm_native_fence_bank32
END LIBRARY
